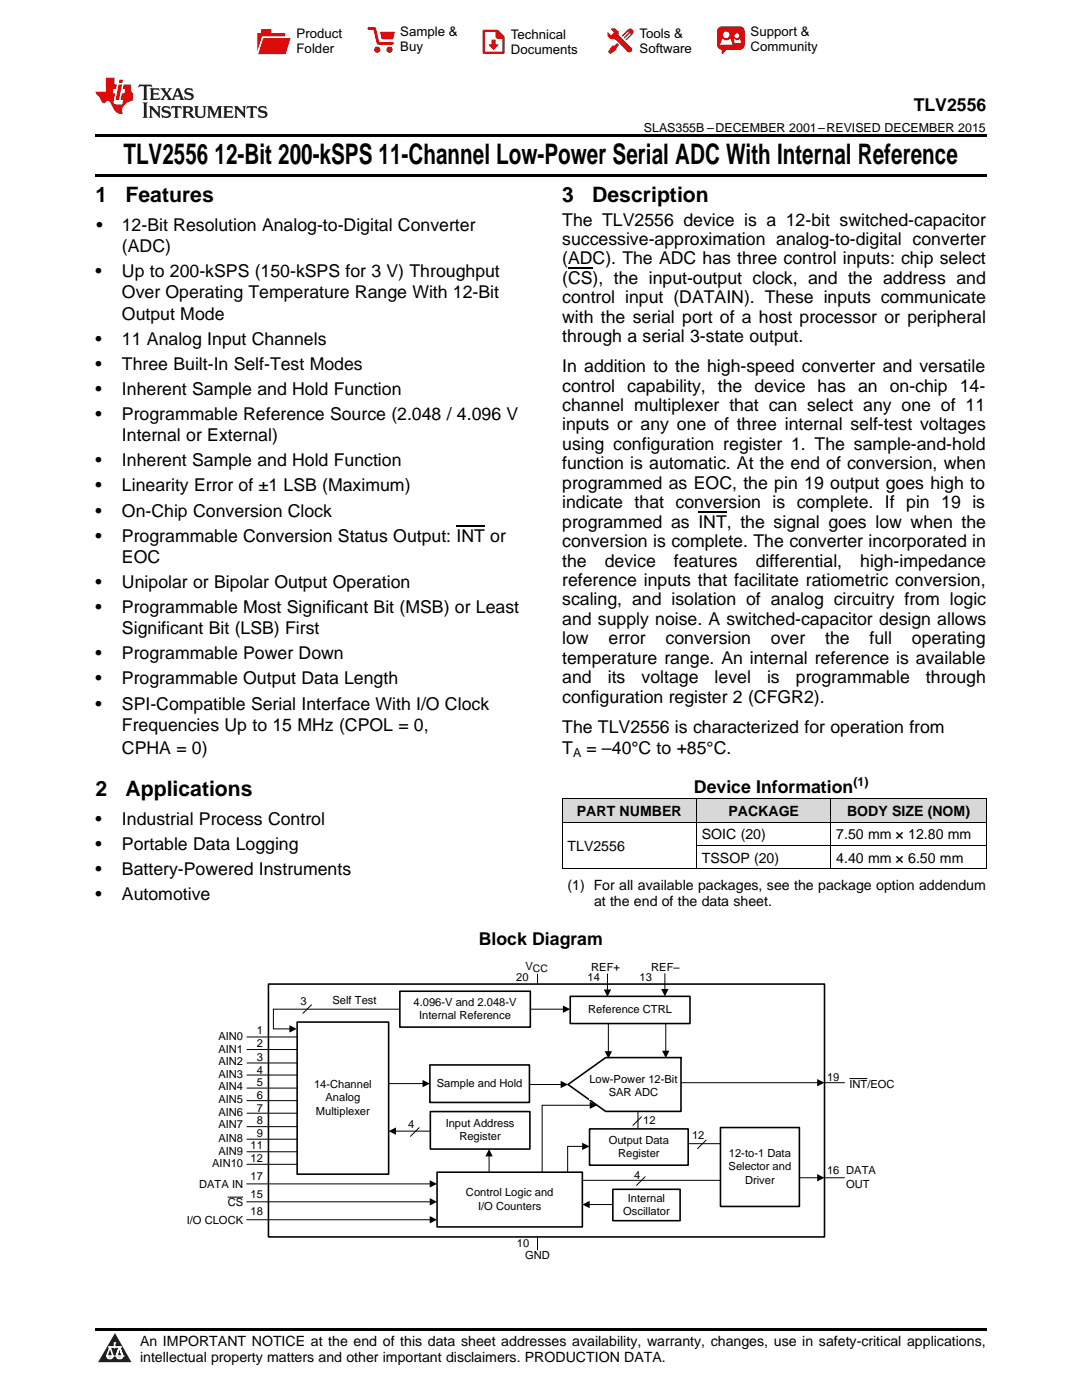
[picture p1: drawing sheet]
<svg xmlns="http://www.w3.org/2000/svg" width="216mm" height="279mm" viewBox="0 0 216 279" stroke-linecap="round" stroke-linejoin="round" font-family="sans-serif">
<defs><g id="words">
<g font-size="5.6">
<text x="24.6" y="32.8">TLV2556</text>
<text x="42.8" y="32.8">12-Bit 200-kSPS 11-Channel Low-Power Serial ADC With Internal Reference</text>
</g>
<g font-size="4.2">
<text x="19" y="40.4">1</text>
<text x="25" y="40.4">Features</text>
<text x="112.2" y="40.4">3</text>
<text x="118.2" y="40.4">Description</text>
<text x="19" y="158.9">2</text>
<text x="25" y="158.9">Applications</text>
</g>
<g font-size="3.5">
<text x="182.3" y="22.2">TLV2556</text>
<text x="19.2" y="46.1">•</text>
<text x="24.3" y="46.1">12-Bit Resolution Analog-to-Digital Converter</text>
<text x="112.2" y="45">The TLV2556 device is a 12-bit switched-capacitor</text>
<text x="24.3" y="50.3">(ADC)</text>
<text x="112.2" y="48.9">successive-approximation analog-to-digital converter</text>
<text x="112.2" y="52.8">(ADC). The ADC has three control inputs: chip select</text>
<text x="19" y="55.3">•</text>
<text x="24.3" y="55.3">Up to 200-kSPS (150-kSPS for 3 V) Throughput</text>
<text x="24.3" y="59.5">Over Operating Temperature Range With 12-Bit</text>
<text x="112.2" y="56.7">(CS), the input-output clock, and the address and</text>
<text x="24.3" y="63.8">Output Mode</text>
<text x="112.2" y="60.5">control input (DATAIN). These inputs communicate</text>
<text x="112.2" y="64.4">with the serial port of a host processor or peripheral</text>
<text x="19" y="68.8">•</text>
<text x="24.3" y="68.8">11 Analog Input Channels</text>
<text x="112.2" y="68.3">through a serial 3-state output.</text>
<text x="19" y="73.8">•</text>
<text x="24.3" y="73.8">Three Built-In Self-Test Modes</text>
<text x="112.2" y="74.3">In addition to the high-speed converter and versatile</text>
<text x="19" y="78.8">•</text>
<text x="19" y="83.8">•</text>
<text x="24.3" y="78.8">Inherent Sample and Hold Function</text>
<text x="24.3" y="83.8">Programmable Reference Source (2.048 / 4.096 V</text>
<text x="112.2" y="78.1">control capability, the device has an on-chip 14-</text>
<text x="112.2" y="82">channel multiplexer that can select any one of 11</text>
<text x="24.3" y="88.1">Internal or External)</text>
<text x="112.2" y="85.9">inputs or any one of three internal self-test voltages</text>
<text x="112.2" y="89.8">using configuration register 1. The sample-and-hold</text>
<text x="19" y="93.1">•</text>
<text x="24.3" y="93.1">Inherent Sample and Hold Function</text>
<text x="112.2" y="93.7">function is automatic. At the end of conversion, when</text>
<text x="19" y="98.1">•</text>
<text x="24.3" y="98.1">Linearity Error of ±1 LSB (Maximum)</text>
<text x="112.2" y="97.5">programmed as EOC, the pin 19 output goes high to</text>
<text x="112.2" y="101.4">indicate that conversion is complete. If pin 19 is</text>
<text x="19" y="103.1">•</text>
<text x="24.3" y="103.1">On-Chip Conversion Clock</text>
<text x="112.2" y="105.3">programmed as INT, the signal goes low when the</text>
<text x="19" y="108.1">•</text>
<text x="24.3" y="108.1">Programmable Conversion Status Output: INT or</text>
<text x="24.3" y="112.3">EOC</text>
<text x="112.2" y="109.2">conversion is complete. The converter incorporated in</text>
<text x="112.2" y="113.1">the</text>
<text x="120.7" y="113.1">device</text>
<text x="134.5" y="113.1">features</text>
<text x="150.8" y="113.1">differential,</text>
<text x="171.7" y="113.1">high-impedance</text>
<text x="19" y="117.3">•</text>
<text x="24.3" y="117.3">Unipolar or Bipolar Output Operation</text>
<text x="112.2" y="116.9">reference inputs that facilitate ratiometric conversion,</text>
<text x="19" y="122.3">•</text>
<text x="24.3" y="122.3">Programmable Most Significant Bit (MSB) or Least</text>
<text x="112.2" y="120.8">scaling, and isolation of analog circuitry from logic</text>
<text x="112.2" y="124.7">and supply noise. A switched-capacitor design allows</text>
<text x="19" y="131.6">•</text>
<text x="24.3" y="126.6">Significant Bit (LSB) First</text>
<text x="24.3" y="131.6">Programmable Power Down</text>
<text x="112.2" y="128.6">low</text>
<text x="121.4" y="128.6">error</text>
<text x="132.8" y="128.6">conversion</text>
<text x="153.8" y="128.6">over</text>
<text x="164.6" y="128.6">the</text>
<text x="173.5" y="128.6">full</text>
<text x="182" y="128.6">operating</text>
<text x="19" y="136.6">•</text>
<text x="24.3" y="136.6">Programmable Output Data Length</text>
<text x="112.2" y="132.5">temperature range. An internal reference is available</text>
<text x="112.2" y="136.3">and</text>
<text x="121.3" y="136.3">its</text>
<text x="128" y="136.3">voltage</text>
<text x="142.6" y="136.3">level</text>
<text x="153.1" y="136.3">is</text>
<text x="158.8" y="136.3">programmable</text>
<text x="184.8" y="136.3">through</text>
<text x="19" y="141.6">•</text>
<text x="24.3" y="141.6">SPI-Compatible Serial Interface With I/O Clock</text>
<text x="112.2" y="140.2">configuration register 2 (CFGR2).</text>
<text x="24.3" y="145.8">Frequencies Up to 15 MHz (CPOL = 0,</text>
<text x="112.2" y="146.2">The TLV2556 is characterized for operation from</text>
<text x="24.3" y="150.5">CPHA = 0)</text>
<text x="112.2" y="150.5">T</text>
<text x="117" y="150.5">= –40°C to +85°C.</text>
<text x="138.5" y="158.2">Device Information</text>
<text x="19" y="164.6">•</text>
<text x="24.3" y="164.6">Industrial Process Control</text>
<text x="19" y="169.6">•</text>
<text x="24.3" y="169.6">Portable Data Logging</text>
<text x="19" y="174.6">•</text>
<text x="19" y="179.6">•</text>
<text x="24.3" y="174.6">Battery-Powered Instruments</text>
<text x="24.3" y="179.6">Automotive</text>
<text x="95.5" y="188.6">Block Diagram</text>
</g>
<g font-size="2.8">
<text x="115.1" y="162.8">PART NUMBER</text>
<text x="140.1" y="167.5">SOIC (20)</text>
<text x="145.3" y="162.8">PACKAGE</text>
<text x="166.9" y="167.5">7.50 mm × 12.80 mm</text>
<text x="169" y="162.8">BODY SIZE (NOM)</text>
<text x="113.2" y="169.8">TLV2556</text>
<text x="140.1" y="172.2">TSSOP (20)</text>
<text x="166.9" y="172.2">4.40 mm × 6.50 mm</text>
<text x="113.2" y="177.7">(1) For all available packages, see the package option addendum</text>
<text x="118.5" y="180.8">at the end of the data sheet.</text>
<text x="27.9" y="268.6">An IMPORTANT NOTICE at the end of this data sheet addresses availability, warranty, changes, use in safety-critical applications,</text>
<text x="27.9" y="271.8">intellectual property matters and other important disclaimers. PRODUCTION DATA.</text>
</g>
<g font-size="2.6">
<text x="59.2" y="7.6">Product</text>
<text x="59.2" y="10.6">Folder</text>
<text x="79.9" y="7.3">Sample &amp;</text>
<text x="79.9" y="10.2">Buy</text>
<text x="101.9" y="7.8">Technical</text>
<text x="101.9" y="10.8">Documents</text>
<text x="127.6" y="7.6">Tools &amp;</text>
<text x="127.6" y="10.6">Software</text>
<text x="149.8" y="7.2">Support &amp;</text>
<text x="149.8" y="10.2">Community</text>
</g>
<g font-size="2.5">
<text x="128.5" y="26.3">SLAS355B –DECEMBER 2001–REVISED DECEMBER 2015</text>
<text x="114.3" y="151.2">A</text>
<text x="170.3" y="156.8">(1)</text>
</g>
<g font-size="2.2">
<text x="103" y="195.8">20</text>
<text x="104.8" y="193.6">VCC</text>
<text x="117.2" y="195.8">14</text>
<text x="118" y="193.8">REF+</text>
<text x="127.6" y="195.8">13</text>
<text x="130" y="193.8">REF±</text>
<text x="60" y="200.6">3</text>
<text x="66.4" y="200.4">Self Test</text>
<text x="82.5" y="200.7">4.096-V and 2.048-V</text>
<text x="83.6" y="203.4">Internal Reference</text>
<text x="117.4" y="202.2">Reference CTRL</text>
<text x="43.6" y="207.6">AIN0</text>
<text x="51.2" y="206.4">1</text>
<text x="51.2" y="209">2</text>
<text x="43.6" y="210.1">AIN1</text>
<text x="43.6" y="212.6">AIN2</text>
<text x="43.6" y="215.2">AIN3</text>
<text x="51.2" y="211.7">3</text>
<text x="51.2" y="214.2">4</text>
<text x="165" y="215.7">19</text>
<text x="43.6" y="217.6">AIN4</text>
<text x="43.6" y="220.2">AIN5</text>
<text x="51.2" y="216.7">5</text>
<text x="51.2" y="219.3">6</text>
<text x="51.2" y="221.9">7</text>
<text x="62.7" y="217.1">14-Channel</text>
<text x="65" y="219.8">Analog</text>
<text x="87.2" y="216.9">Sample and Hold</text>
<text x="117.6" y="216.1">Low-Power 12-Bit</text>
<text x="121.5" y="218.8">SAR ADC</text>
<text x="169.5" y="217.1">INT/EOC</text>
<text x="43.6" y="222.6">AIN6</text>
<text x="43.6" y="225.2">AIN7</text>
<text x="43.6" y="227.8">AIN8</text>
<text x="51.2" y="224.4">8</text>
<text x="51.2" y="226.9">9</text>
<text x="63" y="222.5">Multiplexer</text>
<text x="81.4" y="225.2">4</text>
<text x="88.9" y="224.9">Input Address</text>
<text x="91.7" y="227.6">Register</text>
<text x="128.3" y="224.3">12</text>
<text x="138.1" y="227.3">12</text>
<text x="42.3" y="232.9">AIN10</text>
<text x="43.6" y="230.5">AIN9</text>
<text x="50" y="229.4">11</text>
<text x="50" y="231.9">12</text>
<text x="121.5" y="228.2">Output Data</text>
<text x="123.3" y="230.9">Register</text>
<text x="145.4" y="233.6">Selector and</text>
<text x="145.4" y="230.9">12-to-1 Data</text>
<text x="39.7" y="237.1">DATA IN</text>
<text x="50" y="235.5">17</text>
<text x="50" y="239.1">15</text>
<text x="93" y="238.7">Control Logic and</text>
<text x="125.3" y="239.8">Internal</text>
<text x="126.5" y="235.2">4</text>
<text x="148.7" y="236.2">Driver</text>
<text x="165" y="234.3">16 DATA</text>
<text x="168.8" y="237.1">OUT</text>
<text x="37.3" y="244.3">I/O CLOCK</text>
<text x="45.4" y="240.8">CS</text>
<text x="50" y="242.6">18</text>
<text x="95.4" y="241.4">I/O Counters</text>
<text x="124.4" y="242.5">Oscillator</text>
<text x="103.2" y="248.9">10</text>
<text x="104.8" y="251.3">GND</text>
</g>
</g></defs>
<g fill="#d8d8d8">
<path d="M112.2 159.5h26.8v4.6h-26.8z"/>
<path d="M139 159.5h26.8v4.6h-26.8z"/>
<path d="M165.8 159.5h31v4.6h-31z"/>
</g>
<path d="M22.9 266l3.3 5.9h-6.6z" fill="#231f20"/>
<path d="M21.3 270.6h1.2l-.3 .5h-.3a.53 .53 0 0 1-.6-.5z" fill-rule="evenodd" fill="#fff"/>
<path d="M21.3 270.6h1.2l-.3 .5h-.3a.53 .53 0 0 1-.6-.5z" fill="none" stroke="#231f20" stroke-width=".33"/>
<path d="M21.3 270.6l1.2 .1-.3 .4h-.5z" fill="none" stroke="#fff" stroke-width=".33"/>
<path d="M22.9 268.9h.1" fill="none" stroke="#fff" stroke-width=".33"/>
<path d="M22.9 268v.9z" fill="#fff"/>
<path d="M22.9 268v.9z" fill="none" stroke="#fff" stroke-width=".33"/>
<circle cx="22.9" cy="268" r=".16" fill="#fff"/>
<path d="M21.8 268.8h.1" fill="none" stroke="#fff" stroke-width=".33"/>
<path d="M21.8 268.8h2.2z" fill="#fff"/>
<path d="M21.8 268.8h2.2z" fill="none" stroke="#fff" stroke-width=".33"/>
<circle cx="24" cy="268.8" r=".16" fill="#fff"/>
<path d="M23.2 270.6h.1" fill="none" stroke="#fff" stroke-width=".33"/>
<path d="M23.8 268.8l-.6 1.8z" fill="#fff"/>
<path d="M23.8 268.8l-.6 1.8z" fill="none" stroke="#fff" stroke-width=".33"/>
<path d="M23.8 268.8l.7 1.8z" fill="#fff"/>
<path d="M23.8 268.8l.7 1.8z" fill="none" stroke="#fff" stroke-width=".33"/>
<path d="M24.4 270.6h.1" fill="none" stroke="#fff" stroke-width=".33"/>
<circle cx="21.3" cy="270.6" r=".16" fill="#fff"/>
<path d="M22 268.8l-.7 1.8z" fill="#fff"/>
<path d="M22 268.8l-.7 1.8z" fill="none" stroke="#fff" stroke-width=".33"/>
<path d="M22 268.8l.5 1.8z" fill="#fff"/>
<path d="M22 268.8l.5 1.8z" fill="none" stroke="#fff" stroke-width=".33"/>
<circle cx="22.5" cy="270.6" r=".16" fill="#fff"/>
<path d="M23.3 270.6h1.2a.63 .63 0 0 1-.6 .5 .63 .63 0 0 1-.6-.5z" fill-rule="evenodd" fill="#fff"/>
<path d="M23.3 270.6h1.2a.63 .63 0 0 1-.6 .5 .63 .63 0 0 1-.6-.5z" fill="none" stroke="#231f20" stroke-width=".33"/>
<path d="M23.3 270.6h1.2l-.4 .5h-.5z" fill="none" stroke="#fff" stroke-width=".33"/>
<path d="M23.2 270.6h.1" fill="none" stroke="#fff" stroke-width=".33"/>
<circle cx="24.5" cy="270.6" r=".16" fill="#fff"/>
<path d="M19 265.1h177.8v.5h-177.8z" fill="#000"/>
<path d="M53.6 196.4h110.9v50.5h-110.9zM79.8 197.8h26v7.2h-26zM113.8 198.8h23.9v5.5h-23.9zM59.3 204h18.2v30.3h-18.2zM85.8 212.5h19.8v7.5h-19.8zM113.3 216.4l7.6-5.3h15v10.7h-15zM85.9 221.8h19.8v7.5h-19.8zM87.2 233.9h29v11h-29zM117.6 225.3h19.7v7.2h-19.7zM122.3 237.4h13.4v6.2h-13.4zM143.8 225h15.7v15.8h-15.7z" fill="none" stroke="#000" stroke-width=".32"/>
<path d="M117.6 214.1h17.6v5.4h-17.6z" fill-rule="evenodd" fill="#fff"/>
<g fill="none" stroke="#000" stroke-width=".2">
<path d="M112.2 159.4h84.6M112.2 159.5v13.9M138.9 159.5v13.9M165.8 159.5v13.9M196.8 159.5v13.9M112.2 173.4h84.6M112.2 164.1h84.6M139 168.7h57.8M107.3 194.4v1.8M121.2 194.4v3.3M132.7 194.3v3.3M49.3 207h10"/>
<path d="M49.3 209.5h10M49.3 212.1h10M49.3 214.5h10M49.3 217.2h10M49.3 219.7h10M54.6 205.3h3.3M62.2 200.5l-1.8 1.7M77.6 216.3h6.9M79.8 201.4h-25.2v3.9M105.6 216.4h6.5M105.8 201.4h6.7M121.4 204.4v5.6"/>
<path d="M132.8 204.3v5.6M136 216.1h27.2M164.5 216.1h4M169.5 215.3h3.6M45.4 238.9h3.1M49.2 236.3h36.7M49.2 239.8h36.7M49.3 222.2h10M49.3 224.8h10M49.3 227.4h10M49.3 229.9h10M49.3 232.4h10"/>
<path d="M78.8 225.7h7M83.6 225.1l-1.7 1.7M97.6 230.6v3.3M116.2 235.6h27.5M116.4 228.8h-3.1v5.1M117.9 220.6h-9.7v13.4M127.3 221.8v3.4M128 222.9l-1.7 1.7M128.7 234.8l-1.7 1.8M137.3 228.2h6.5M140.9 227.5l-1.7 1.7M159.7 235h3.5"/>
<path d="M164.5 235h4M49.2 243.4h36.7M107.3 246.8v2.7M117.5 240.4h4.7"/>
</g>
<g fill="#000">
<path d="M120.5 197.5h1.4l-.7 1.4zM131.9 197.4h1.5l-.7 1.4zM57.8 204.6l1.4 .7-1.4 .8zM84.3 215.5l1.5 .8-1.5 .7zM111.9 215.7l1.4 .7-1.4 .8zM112.3 200.7l1.5 .7-1.5 .7zM117.7 219.8l1.4 .8-1.4 .7zM120.7 209.8h1.4l-.7 1.5zM132.1 209.7h1.5l-.8 1.5zM163.1 215.3l1.4 .8-1.4 .7zM77.5 225.7l1.5-.7v1.5zM85.7 235.5l1.5 .8-1.5 .7z"/>
<path d="M85.7 239.1l1.5 .7-1.5 .8zM97.6 229.3l.7 1.5h-1.4zM116.2 228.1l1.4 .7-1.4 .7zM163.1 234.3l1.4 .7-1.4 .8zM85.7 242.7l1.5 .7-1.5 .8zM116.2 240.4l1.5-.7v1.4z"/>
</g>
<path d="M19 34.8h177.8v.5h-177.8zM19 26.8h177.8v.6h-177.8z" fill="#000"/>
<path d="M27.7 16.9l-.1 .6 .6-.3h.5v.2v2.2l-.2 .4h1l-.2-.4v-2.2v-.2h.5l.6 .3-.2-.6zM29.9 17.6l.2 .4v1.6l-.2 .4h1.9l.1-.6a1.09 1.09 0 0 1-1.3 .1v-.6h.6l.4 .2v-.7l-.2 .2h-.8v-.6l.2-.1a1.01 1.01 0 0 1 1 .3l-.1-.6zM32 17.6l.9 1.2-1 1.2h.9l-.2-.3 .5-.7 .5 .7-.3 .3h1.7l-.2-.3 .1-.4h1l.1 .4-.2 .3h1l-.3-.4-.7-2h-.5l-1 2.2-.8-1.1 .9-1.1h-.9l.2 .2-.4 .7-.4-.7 .2-.2zM35.4 18l.4 1h-.8zM37 17.7a.66 .66 0 0 0-.2 .8 .66 .66 0 0 0 .6 .4l.7 .2 .1 .2a.8 .8 0 0 1-.7 .4 .8 .8 0 0 1-.7-.5l.1 .8 .2-.2a.94 .94 0 0 0 1.1 .1 .94 .94 0 0 0 .4-.9 1.48 1.48 0 0 0-1.3-.6v-.4a1.1 1.1 0 0 1 1.2 .2l-.2-.6-.2 .1-.5-.1zM28.5 20.4l.2 .4v2.3l-.2 .4h1l-.2-.4v-2.3l.2-.4zM29.7 21.2l.2 .4v1.5l-.2 .4h.8l-.3-.4 .1-1.3 1.6 1.8v-2l.2-.4h-.7l.2 .2v1.1l-1.2-1.3zM32.5 21.3a.66 .66 0 0 0-.2 .8 .66 .66 0 0 0 .6 .4l.6 .2 .2 .2a.8 .8 0 0 1-.8 .4 .8 .8 0 0 1-.7-.5l.2 .7 .2-.1a.94 .94 0 0 0 1 .1 .94 .94 0 0 0 .5-1 1.47 1.47 0 0 0-1.3-.6l-.1-.3a1.1 1.1 0 0 1 1.3 .2l-.2-.6-.2 .1-.5-.2zM34.3 21.2l-.2 .6a.64 .64 0 0 1 .8-.3v1.6l-.2 .4h1l-.3-.4 .1-1.6a.66 .66 0 0 1 .8 .3l-.2-.6zM36.3 21.2l.3 .4v1.5l-.3 .4h1l-.2-.2v-.7h.5l.1 .1a.8 .8 0 0 0 1.2 .7l-1-1a.62 .62 0 0 0 .6-.5 .62 .62 0 0 0-.6-.7zM37.1 21.5h.1a.48 .48 0 0 1 .6 0 .48 .48 0 0 1 .1 .6l-.2 .1-.6 .1zM38.7 21.2l.2 .2a2.29 2.29 0 0 0 .4 2 1.05 1.05 0 0 0 1.7-.7v-1.3l.2-.2h-.8l.2 .4v1.1a.61 .61 0 0 1-.6 .6 .61 .61 0 0 1-.6-.6v-1.1l.3-.4zM41.3 21.2l.3 .4v1.5l-.3 .4h.8l-.2-.4v-1.4l.8 1.9 .9-1.9v1.4l-.2 .4h.9l-.2-.4v-1.5l.2-.4h-.8l-.7 1.5-.6-1.5zM44.5 21.2l.2 .4v1.5l-.2 .4h1.9l.2-.6a1.1 1.1 0 0 1-1.4 .2v-.7h.6l.4 .2v-.6l-.2 .1-.8 .1v-.6l.2-.1a1.02 1.02 0 0 1 1.1 .2l-.2-.5zM46.7 21.2l.2 .4v1.5l-.2 .4h.8l-.3-.4 .1-1.3 1.6 1.8v-2l.2-.4h-.7l.2 .2v1.1l-1.2-1.3zM49.3 21.2l-.1 .6a.64 .64 0 0 1 .8-.3v1.6l-.3 .4h1l-.2-.4v-1.6a.66 .66 0 0 1 .8 .3l-.1-.6zM51.7 21.3a.66 .66 0 0 0-.2 .7 .66 .66 0 0 0 .7 .5l.6 .2 .1 .2a.8 .8 0 0 1-.7 .4 .8 .8 0 0 1-.7-.5l.1 .7 .2-.1a.94 .94 0 0 0 1.1 .1 .94 .94 0 0 0 .4-1 1.48 1.48 0 0 0-1.2-.6l-.1-.3a1.1 1.1 0 0 1 1.2 .2l-.2-.6-.1 .1-.6-.2z" fill="#231f20"/>
<path d="M21.1 15.5v2.8h-2v.4l.9 .9a.96 .96 0 0 0 1 1 .59 .59 0 0 1 .5-.4 .59 .59 0 0 1 .5 .3l.4 .8a1.61 1.61 0 0 0 2.1 1.3 1.63 1.63 0 0 1 1.1-2.2l.9-.3v-1.5a1.6 1.6 0 0 1-.4-1.7h-1.4l-.2 .9h.5l-.2 .8h-.5l-.2 1v.3h.5l-.2 .9h-.7a.74 .74 0 0 1-1-.6l.3-1.6h-.5l.2-.8h.5l.1-.9h-.4v-1.4zM23.7 16.9l-.7 3h.8l.6-3zM23.8 15.9l-.1 .7h.7l.2-.7z" fill="#ee1d23"/>
<g fill="#d60000">
<path d="M52.1 5.8h2v.8h2.8v4.2h-5.5v-4.2h.7z" fill-rule="evenodd"/>
<path d="M52.4 7.5h5.6l-1 3.3h-5.6z" fill-rule="evenodd"/>
</g>
<path d="M52.4 7.4h5.7l-.1 .1h-5.5l-1.1 3.3z" fill-rule="evenodd" fill="#fff"/>
<path d="M52.4 7.4h5.7l-.1 .1h-5.5l-1.1 3.3z" fill="none" stroke="#fff" stroke-width=".2"/>
<path d="M73.6 5.7h1.1l.7 2.9h2.9" fill="none" stroke="#d60000" stroke-width=".55"/>
<g fill="#d60000">
<path d="M75.8 6.3h3l-.4 1.6h-2.2z" fill-rule="evenodd"/>
<circle cx="75.3" cy="9.9" r=".62"/>
<circle cx="77.7" cy="9.9" r=".62"/>
</g>
<path d="M96.5 6.2h2.7l1.3 1.2v3.1h-4z" fill="none" stroke="#d60000" stroke-width=".44"/>
<g fill="#d60000">
<path d="M98.1 7.9h.8v1h.5l-.9 1.1-1-1v-.1h.6z" fill-rule="evenodd"/>
<path d="M98.9 6.2h.3l1.3 1.2v.4h-1.3l-.3-.4z" fill-rule="evenodd"/>
<path d="M121.9 5.7h.8l.7 .6 .1 .7 2.5 2.5-.8 .8-2.3-2.3-1.1-.2-.6-.6v-.8l.7 .6 .5-.4v-.2l-.5-.5z" fill-rule="evenodd"/>
<path d="M122.2 9.1h.4l.5-.5 .4 .4-.5 .5v.4l-1.2 .9-.5-.5z" fill-rule="evenodd"/>
<path d="M125.3 5.9a.67 .67 0 0 1 .9 0 .67 .67 0 0 1 0 .9z" fill-rule="evenodd"/>
<path d="M125.3 5.9l.9 .9-1.2 1.2h-.2v-.2l1-.9v-.2h-.2l-.9 1h-.2v-.2l.9-1 .1-.2h-.3l-.9 1h-.2v-.2z" fill-rule="evenodd"/>
<circle cx="125.6" cy="9.9" r=".54"/>
</g>
<path d="M123.3 6.3v.7" fill="none" stroke="#d60000" stroke-width=".2"/>
<g fill="#d60000">
<path d="M143.4 5.5l.6-.2h3.6a.95 .95 0 0 1 1 .9v2.8a.95 .95 0 0 1-1 .9h-3.6a.95 .95 0 0 1-.9-.9v-2.8z" fill-rule="evenodd"/>
<path d="M144 9.9h.9l-.7 .9h-.2z" fill-rule="evenodd"/>
</g>
<g fill="#fff">
<path d="M146.6 8.6h1.3z"/>
<path d="M144.1 7.8h.3l.1 .2h.8l.2-.2h.3l.4 1.1h-2.5z" fill-rule="evenodd"/>
<path d="M146.4 7.8h.3l.1 .2h.5l.2-.2h.2l.2 .8h-1.3z" fill-rule="evenodd"/>
<circle cx="144.9" cy="6.9" r=".65"/>
<circle cx="147" cy="7.1" r=".48"/>
</g>
<path d="M113.3 53.5h4.9M91.1 105h5.7M139.3 102.2h5.7" fill="none" stroke="#000" stroke-width=".25"/>
<use href="#words"/>
</svg>
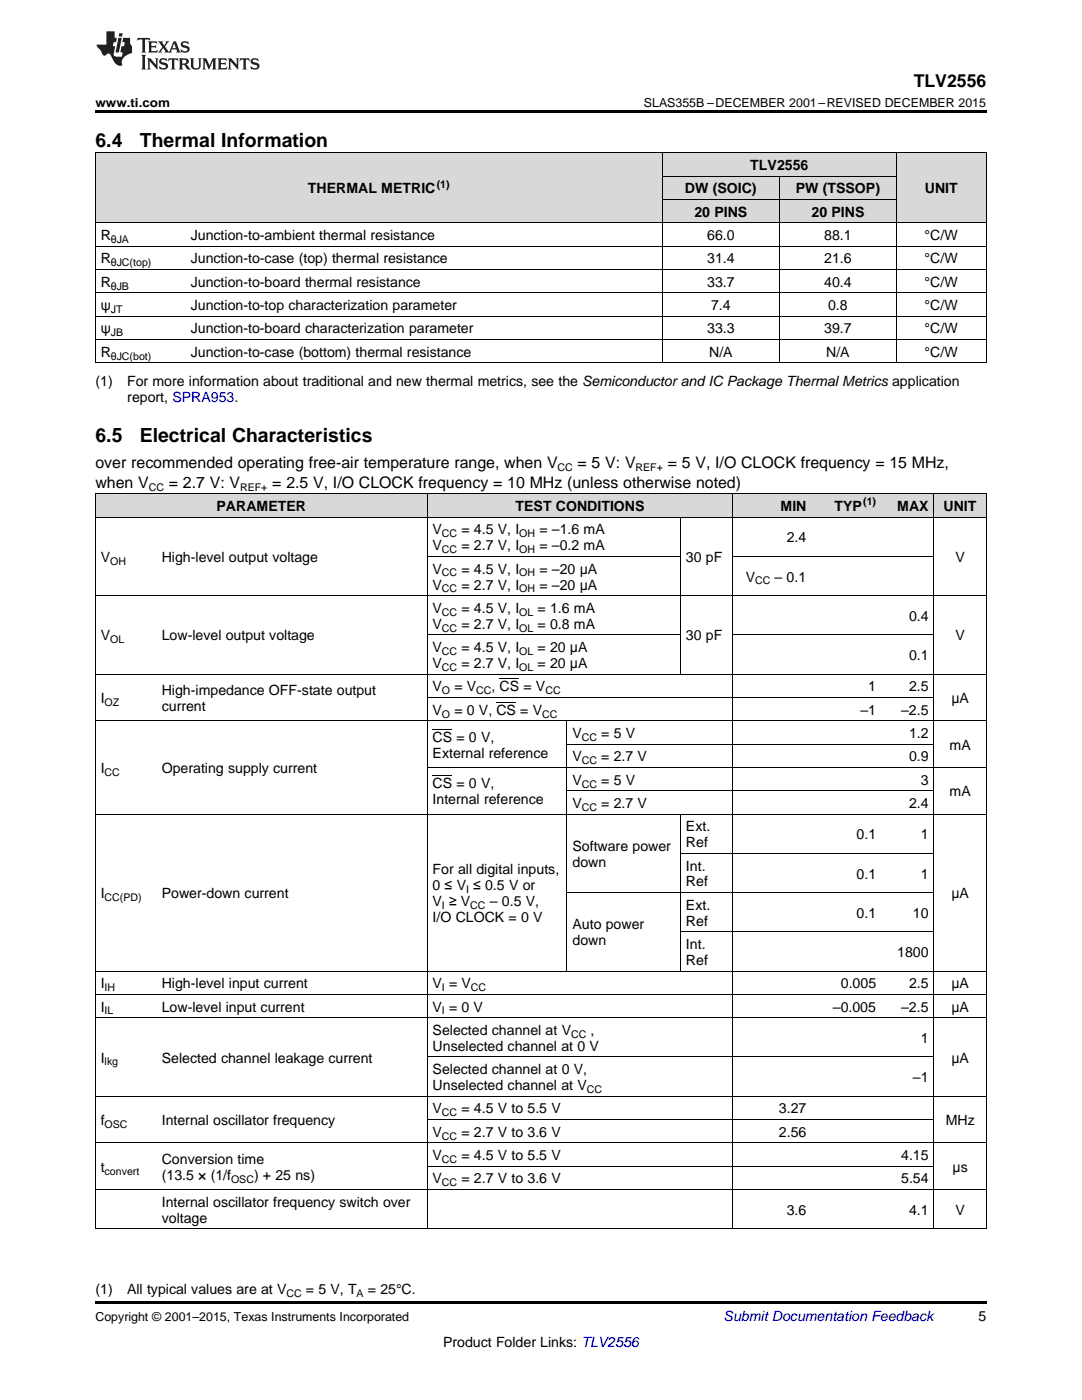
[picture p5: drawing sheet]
<svg xmlns="http://www.w3.org/2000/svg" width="216mm" height="279mm" viewBox="0 0 216 279" stroke-linecap="round" stroke-linejoin="round" font-family="sans-serif">
<defs><g id="words">
<g font-size="3.9">
<text x="19" y="29.3">6.4</text>
<text x="27.9" y="29.3">Thermal Information</text>
<text x="19" y="88.3">6.5</text>
<text x="27.9" y="88.3">Electrical Characteristics</text>
</g>
<text font-size="3.5" x="182.3" y="17.3">TLV2556</text>
<g font-size="3.2">
<text x="19" y="93.5">over recommended operating free-air temperature range, when V</text>
<text x="115.3" y="93.5">= 5 V: V</text>
<text x="133.2" y="93.5">= 5 V, I/O CLOCK frequency = 15 MHz,</text>
<text x="19" y="97.3">when V</text>
<text x="33.7" y="97.3">= 2.7 V: V</text>
<text x="54.3" y="97.3">= 2.5 V, I/O CLOCK frequency = 10 MHz (unless otherwise noted)</text>
</g>
<g font-size="2.8">
<text x="149.7" y="33.9">TLV2556</text>
<text x="61.5" y="38.6">THERMAL METRIC</text>
<text x="136.7" y="38.6">DW (SOIC)</text>
<text x="158.8" y="38.6">PW (TSSOP)</text>
<text x="184.5" y="38.6">UNIT</text>
<text x="20.1" y="47.9">R</text>
<text x="38.1" y="47.9">Junction-to-ambient thermal resistance</text>
<text x="138.6" y="43.3">20 PINS</text>
<text x="141.1" y="47.9">66.0</text>
<text x="161.9" y="43.3">20 PINS</text>
<text x="164.5" y="47.9">88.1</text>
<text x="184.5" y="47.9">°C/W</text>
<text x="20.1" y="52.6">R</text>
<text x="38.1" y="52.6">Junction-to-case (top) thermal resistance</text>
<text x="141.1" y="52.6">31.4</text>
<text x="164.5" y="52.6">21.6</text>
<text x="184.5" y="52.6">°C/W</text>
<text x="20.1" y="57.2">R</text>
<text x="38.1" y="57.2">Junction-to-board thermal resistance</text>
<text x="141.1" y="57.2">33.7</text>
<text x="164.5" y="57.2">40.4</text>
<text x="184.5" y="57.2">°C/W</text>
<text x="20.1" y="61.9">ψ</text>
<text x="38.1" y="61.9">Junction-to-top characterization parameter</text>
<text x="141.9" y="61.9">7.4</text>
<text x="165.2" y="61.9">0.8</text>
<text x="184.5" y="61.9">°C/W</text>
<text x="20.1" y="66.5">ψ</text>
<text x="20.1" y="71.2">R</text>
<text x="38.1" y="66.5">Junction-to-board characterization parameter</text>
<text x="38.1" y="71.2">Junction-to-case (bottom) thermal resistance</text>
<text x="141.1" y="66.5">33.3</text>
<text x="141.5" y="71.2">N/A</text>
<text x="164.5" y="66.5">39.7</text>
<text x="164.9" y="71.2">N/A</text>
<text x="184.5" y="66.5">°C/W</text>
<text x="184.5" y="71.2">°C/W</text>
<text x="19" y="77">(1)</text>
<text x="25.4" y="77">For more information about traditional and new thermal metrics, see the Semiconductor and IC Package Thermal Metrics application</text>
<text x="25.4" y="80.2">report, SPRA953.</text>
<text x="43.2" y="102">PARAMETER</text>
<text x="102.9" y="102">TEST CONDITIONS</text>
<text x="155.8" y="102">MIN</text>
<text x="166.5" y="102">TYP</text>
<text x="179" y="102">MAX</text>
<text x="188.3" y="102">UNIT</text>
<text x="86.3" y="106.6">V</text>
<text x="92.1" y="106.6">= 4.5 V, I</text>
<text x="107.6" y="106.6">= –1.6 mA</text>
<text x="20.1" y="112.1">V</text>
<text x="32.3" y="112.1">High-level output voltage</text>
<text x="86.3" y="109.8">V</text>
<text x="92.1" y="109.8">= 2.7 V, I</text>
<text x="107.6" y="109.8">= –0.2 mA</text>
<text x="136.9" y="112.1">30 pF</text>
<text x="157" y="108.2">2.4</text>
<text x="190.6" y="112.1">V</text>
<text x="86.3" y="114.5">V</text>
<text x="86.3" y="117.7">V</text>
<text x="92.1" y="114.5">= 4.5 V, I</text>
<text x="92.1" y="117.7">= 2.7 V, I</text>
<text x="107.6" y="114.5">= –20 μA</text>
<text x="107.6" y="117.7">= –20 μA</text>
<text x="148.8" y="116.1">V</text>
<text x="154.6" y="116.1">– 0.1</text>
<text x="86.3" y="122.3">V</text>
<text x="86.3" y="125.5">V</text>
<text x="92.1" y="122.3">= 4.5 V, I</text>
<text x="92.1" y="125.5">= 2.7 V, I</text>
<text x="107.3" y="122.3">= 1.6 mA</text>
<text x="107.3" y="125.5">= 0.8 mA</text>
<text x="181.4" y="123.9">0.4</text>
<text x="20.1" y="127.8">V</text>
<text x="32.3" y="127.8">Low-level output voltage</text>
<text x="86.3" y="130.1">V</text>
<text x="92.1" y="130.1">= 4.5 V, I</text>
<text x="107.3" y="130.1">= 20 μA</text>
<text x="136.9" y="127.8">30 pF</text>
<text x="181.4" y="131.7">0.1</text>
<text x="190.6" y="127.8">V</text>
<text x="86.3" y="133.3">V</text>
<text x="86.3" y="138">V</text>
<text x="90.7" y="138">= V</text>
<text x="92.1" y="133.3">= 2.7 V, I</text>
<text x="98.1" y="138">, CS = V</text>
<text x="107.3" y="133.3">= 20 μA</text>
<text x="173.2" y="138">1</text>
<text x="181.4" y="138">2.5</text>
<text x="20.1" y="140.3">I</text>
<text x="32.3" y="138.7">High-impedance OFF-state output</text>
<text x="32.3" y="141.9">current</text>
<text x="86.3" y="142.6">V</text>
<text x="90.7" y="142.6">= 0 V, CS = V</text>
<text x="171.7" y="142.6">–1</text>
<text x="179.8" y="142.6">–2.5</text>
<text x="189.8" y="140.3">μA</text>
<text x="86.3" y="148">CS = 0 V,</text>
<text x="114.2" y="147.3">V</text>
<text x="120" y="147.3">= 5 V</text>
<text x="181.4" y="147.3">1.2</text>
<text x="189.5" y="149.6">mA</text>
<text x="20.1" y="154.3">I</text>
<text x="32.3" y="154.3">Operating supply current</text>
<text x="86.3" y="151.2">External reference</text>
<text x="114.2" y="151.9">V</text>
<text x="120" y="151.9">= 2.7 V</text>
<text x="181.4" y="151.9">0.9</text>
<text x="86.3" y="157.3">CS = 0 V,</text>
<text x="86.3" y="160.5">Internal reference</text>
<text x="114.2" y="156.6">V</text>
<text x="114.2" y="161.3">V</text>
<text x="120" y="156.6">= 5 V</text>
<text x="120" y="161.3">= 2.7 V</text>
<text x="181.4" y="161.3">2.4</text>
<text x="183.7" y="156.6">3</text>
<text x="189.5" y="158.9">mA</text>
<text x="136.9" y="165.9">Ext.</text>
<text x="170.9" y="167.5">0.1</text>
<text x="183.7" y="167.5">1</text>
<text x="114.2" y="169.8">Software power</text>
<text x="114.2" y="173">down</text>
<text x="136.9" y="169.1">Ref</text>
<text x="136.9" y="173.7">Int.</text>
<text x="20.1" y="179.2">I</text>
<text x="32.3" y="179.2">Power-down current</text>
<text x="86.3" y="174.5">For all digital inputs,</text>
<text x="86.3" y="177.7">0 ≤ V ≤ 0.5 V or</text>
<text x="136.9" y="176.9">Ref</text>
<text x="170.9" y="175.3">0.1</text>
<text x="183.7" y="175.3">1</text>
<text x="189.8" y="179.2">μA</text>
<text x="86.3" y="180.8">V ≥ V</text>
<text x="86.3" y="184">I/O CLOCK = 0 V</text>
<text x="97.7" y="180.8">– 0.5 V,</text>
<text x="114.2" y="185.5">Auto power</text>
<text x="136.9" y="181.6">Ext.</text>
<text x="136.9" y="184.7">Ref</text>
<text x="170.9" y="183.2">0.1</text>
<text x="182.2" y="183.2">10</text>
<text x="114.2" y="188.7">down</text>
<text x="136.9" y="189.4">Int.</text>
<text x="179" y="191">1800</text>
<text x="20.1" y="197.2">I</text>
<text x="32.3" y="197.2">High-level input current</text>
<text x="86.3" y="197.2">V = V</text>
<text x="136.9" y="192.6">Ref</text>
<text x="167.8" y="197.2">0.005</text>
<text x="181.4" y="197.2">2.5</text>
<text x="189.8" y="197.2">μA</text>
<text x="20.1" y="201.9">I</text>
<text x="32.3" y="201.9">Low-level input current</text>
<text x="86.3" y="201.9">V = 0 V</text>
<text x="166.2" y="201.9">–0.005</text>
<text x="179.8" y="201.9">–2.5</text>
<text x="189.8" y="201.9">μA</text>
<text x="86.3" y="206.6">Selected channel at V</text>
<text x="86.3" y="209.7">Unselected channel at 0 V</text>
<text x="117.8" y="206.6">,</text>
<text x="183.7" y="208.1">1</text>
<text x="20.1" y="212.1">I</text>
<text x="32.3" y="212.1">Selected channel leakage current</text>
<text x="86.3" y="214.4">Selected channel at 0 V,</text>
<text x="182.2" y="216">–1</text>
<text x="189.8" y="212.1">μA</text>
<text x="86.3" y="217.6">Unselected channel at V</text>
<text x="20.1" y="224.5">f</text>
<text x="32.3" y="224.5">Internal oscillator frequency</text>
<text x="86.3" y="222.2">V</text>
<text x="86.3" y="226.9">V</text>
<text x="92.1" y="222.2">= 4.5 V to 5.5 V</text>
<text x="92.1" y="226.9">= 2.7 V to 3.6 V</text>
<text x="155.4" y="222.2">3.27</text>
<text x="155.4" y="226.9">2.56</text>
<text x="188.7" y="224.5">MHz</text>
<text x="20.1" y="233.9">t</text>
<text x="32.3" y="232.3">Conversion time</text>
<text x="86.3" y="231.5">V</text>
<text x="92.1" y="231.5">= 4.5 V to 5.5 V</text>
<text x="179.8" y="231.5">4.15</text>
<text x="190.1" y="233.9">μs</text>
<text x="32.3" y="235.4">(13.5 × (1/f</text>
<text x="50.7" y="235.4">) + 25 ns)</text>
<text x="86.3" y="236.2">V</text>
<text x="92.1" y="236.2">= 2.7 V to 3.6 V</text>
<text x="179.8" y="236.2">5.54</text>
<text x="32.3" y="240.8">Internal oscillator frequency switch over</text>
<text x="32.3" y="244">voltage</text>
<text x="157" y="242.4">3.6</text>
<text x="181.4" y="242.4">4.1</text>
<text x="190.6" y="242.4">V</text>
<text x="19" y="258.2">(1)</text>
<text x="25.4" y="258.2">All typical values are at V</text>
<text x="61" y="258.2">= 5 V, T</text>
<text x="73.4" y="258.2">= 25°C.</text>
<text x="195.3" y="263.6">5</text>
<text x="88.4" y="268.9">Product Folder Links: TLV2556</text>
</g>
<text font-size="2.8" fill="#0000c8" x="144.4" y="263.6">Submit Documentation Feedback</text>
<g font-size="2.5">
<text x="19" y="21.4">www.ti.com</text>
<text x="128.5" y="21.4">SLAS355B –DECEMBER 2001–REVISED DECEMBER 2015</text>
<text x="19" y="263.6">Copyright © 2001–2015, Texas Instruments Incorporated</text>
</g>
<g font-size="2.1">
<text x="87.1" y="37.5">(1)</text>
<text x="22.1" y="48.5">θJA</text>
<text x="22.1" y="53.1">θJC(top)</text>
<text x="22.1" y="57.8">θJB</text>
<text x="22.1" y="62.4">JT</text>
<text x="22.1" y="67.1">JB</text>
<text x="22.1" y="71.8">θJC(bot)</text>
<text x="111.3" y="94.1">CC</text>
<text x="126.8" y="94.1">REF+</text>
<text x="29.7" y="98">CC</text>
<text x="47.9" y="98">REF+</text>
<text x="172.2" y="100.9">(1)</text>
<text x="88.2" y="107.2">CC</text>
<text x="103.6" y="107.2">OH</text>
<text x="22" y="112.7">OH</text>
<text x="88.2" y="110.4">CC</text>
<text x="103.6" y="110.4">OH</text>
<text x="88.2" y="115">CC</text>
<text x="88.2" y="118.2">CC</text>
<text x="103.6" y="115">OH</text>
<text x="103.6" y="118.2">OH</text>
<text x="150.7" y="116.6">CC</text>
<text x="88.2" y="122.9">CC</text>
<text x="103.6" y="122.9">OL</text>
<text x="22" y="128.4">OL</text>
<text x="88.2" y="126">CC</text>
<text x="88.2" y="130.7">CC</text>
<text x="103.6" y="126">OL</text>
<text x="103.6" y="130.7">OL</text>
<text x="88.2" y="133.9">CC</text>
<text x="103.6" y="133.9">OL</text>
<text x="20.9" y="140.9">OZ</text>
<text x="88.2" y="138.5">O</text>
<text x="88.2" y="143.2">O</text>
<text x="95" y="138.5">CC</text>
<text x="108.2" y="143.2">CC</text>
<text x="108.8" y="138.5">CC</text>
<text x="116.1" y="147.8">CC</text>
<text x="20.9" y="154.8">CC</text>
<text x="116.1" y="152.5">CC</text>
<text x="116.1" y="157.2">CC</text>
<text x="116.1" y="161.8">CC</text>
<text x="20.9" y="179.8">CC(PD)</text>
<text x="93" y="178.2">I</text>
<text x="88.2" y="181.4">I</text>
<text x="93.8" y="181.4">CC</text>
<text x="20.9" y="197.8">IH</text>
<text x="88.2" y="197.8">I</text>
<text x="94" y="197.8">CC</text>
<text x="20.9" y="202.5">IL</text>
<text x="88.2" y="202.5">I</text>
<text x="113.9" y="207.1">CC</text>
<text x="20.9" y="212.6">lkg</text>
<text x="117.1" y="218.1">CC</text>
<text x="20.9" y="225.1">OSC</text>
<text x="88.2" y="222.8">CC</text>
<text x="88.2" y="227.4">CC</text>
<text x="88.2" y="232.1">CC</text>
<text x="20.9" y="234.4">convert</text>
<text x="46.1" y="236">OSC</text>
<text x="88.2" y="236.7">CC</text>
<text x="57.1" y="258.8">CC</text>
<text x="71.2" y="258.8">A</text>
</g>
</g></defs>
<g fill="#d8d8d8">
<path d="M19 98.6h12.2v4.7h-12.2z"/>
<path d="M31.2 98.6h31.4v4.7h-31.4z"/>
<path d="M62.6 98.6h22.7v4.7h-22.7z"/>
<path d="M85.3 98.6h27.9v4.7h-27.9z"/>
<path d="M113.2 98.6h22.6v4.7h-22.6z"/>
<path d="M135.8 98.6h10.5v4.7h-10.5z"/>
<path d="M146.3 98.6h15.7v4.7h-15.7z"/>
<path d="M162 98.6h13.9v4.7h-13.9z"/>
<path d="M175.9 98.6h10.5v4.7h-10.5z"/>
<path d="M186.4 98.6h10.4v4.7h-10.4z"/>
<path d="M19 30.6h18v13.9h-18z"/>
<path d="M37 30.6h95.2v13.9h-95.2z"/>
<path d="M132.2 39.9h23.3v4.6h-23.3z"/>
<path d="M155.5 39.9h23.4v4.6h-23.4z"/>
<path d="M178.9 30.6h17.9v13.9h-17.9z"/>
<path d="M132.2 35.2h23.3v4.7h-23.3z"/>
<path d="M155.5 35.2h23.4v4.7h-23.4z"/>
<path d="M132.2 30.6h23.3v4.6h-23.3z"/>
<path d="M155.5 30.6h23.4v4.6h-23.4z"/>
</g>
<path d="M19 22h177.8v.5h-177.8zM19 72.4l.2 .1zM132.1 72.4l.1 .1zM155.4 72.4l.1 .1zM178.8 72.4l.1 .1zM196.7 72.4l.1 .1zM19 259.7h177.8v.5h-177.8z" fill="#000"/>
<g fill="none" stroke="#000" stroke-width=".2">
<path d="M19 30.5h177.8M19.1 30.5v42M132.1 30.5v42M132.2 39.8h46.7M132.2 35.2h46.7M155.5 35.2v37.3M178.8 30.5v42M196.8 30.5v42M19 58.4h177.8M19 53.8h177.8M19 49.1h177.8M19 44.5h177.8"/>
<path d="M19 72.4h177.8M19 67.8h177.8M19 63.1h177.8M19 98.5h177.8M19.1 98.6v146.7M85.2 98.6v146.7M146.2 98.6v146.7M186.3 98.6v146.7M196.8 98.6v146.7M19 118.9h177.8M19 103.2h177.8M85.3 111h50.5"/>
<path d="M135.8 103.2v31.4M146.3 111h40.1M19 134.5h177.8M85.3 139.2h101.1M85.3 126.7h50.5M146.3 126.7h40.1M19 143.8h177.8M85.3 153.2h111.5M113.1 143.9v50M113.2 157.8h73.2M113.2 148.5h73.2M19 162.5h177.8"/>
<path d="M113.2 178.1h73.2M135.8 162.5v31.4M135.8 170.3h50.6M19 198.5h177.8M19 193.8h177.8M135.8 186h50.6M19 218.8h177.8M19 203.1h177.8M85.3 210.9h101.1M19 237.4h177.8M19 228.1h177.8M85.3 232.7h101.1"/>
<path d="M85.3 223.4h101.1M19 245.2h177.8"/>
</g>
<g fill="#231f20">
<path d="M27.5 7.6l-.1 .5 .4-.2h.6v.1v2.1l-.2 .4h1l-.3-.4v-2.1l.1-.1h.5l.5 .2-.2-.5zM29.5 8.3l.2 .3v1.5l-.2 .4h1.8l.2-.6a1.04 1.04 0 0 1-1.3 .2v-.7h.6l.3 .2v-.6l-.3 .2h-.6v-.6l.8-.1 .4 .3-.2-.5zM31.5 8.3l.9 1.1-.9 1.1h.8l-.2-.2 .5-.7 .4 .7-.2 .2h1.5l-.1-.2 .1-.4h.9l.1 .4-.2 .2h1l-.3-.3-.7-1.9h-.5l-.9 2-.8-1 .9-1h-.8l.1 .3-.3 .5-.4-.6 .2-.2zM34.7 8.6l.4 1h-.7zM36.3 8.4a.63 .63 0 0 0-.2 .7 .63 .63 0 0 0 .6 .4l.6 .2 .1 .2a.75 .75 0 0 1-.7 .4 .75 .75 0 0 1-.6-.5l.1 .7 .1-.1a1.11 1.11 0 0 0 1.5-.6 1.13 1.13 0 0 0-1.2-.8l-.1-.4a1.04 1.04 0 0 1 1.2 .2l-.2-.5-.1 .1-.5-.2zM28.2 10.9l.2 .4v2.2l-.2 .4h1l-.3-.4v-2.2l.3-.4zM29.3 11.6l.3 .4v1.5l-.3 .4h.8l-.2-.4v-1.3l1.5 1.7v-1.9l.2-.4h-.7l.2 .4v.9l-1.1-1.3zM32 11.8a.62 .62 0 0 0-.2 .7 .62 .62 0 0 0 .6 .4l.6 .1 .1 .3a.76 .76 0 0 1-.7 .3 .76 .76 0 0 1-.6-.4l.1 .7 .1-.1a1.11 1.11 0 0 0 1.5-.6 1.13 1.13 0 0 0-1.2-.8l-.1-.4a1.04 1.04 0 0 1 1.2 .2l-.2-.6-.1 .1-.5-.1zM33.7 11.6l-.2 .6a.61 .61 0 0 1 .8-.3v1.6l-.2 .4h.9l-.2-.4v-1.6a.63 .63 0 0 1 .8 .3l-.2-.6zM35.6 11.6l.3 .4v1.5l-.3 .4h1l-.2-.2v-.8l.5 .2a.76 .76 0 0 0 1.2 .7l-1-1a.58 .58 0 0 0 .6-.5 .58 .58 0 0 0-.5-.6zM36.4 11.9h.1a.45 .45 0 0 1 .5 .1 .45 .45 0 0 1 .1 .5l-.7 .2zM37.9 11.6l.2 .2a2.17 2.17 0 0 0 .3 1.9 .99 .99 0 0 0 1.6-.6v-1.1l.2-.4h-.7l.2 .2a1.92 1.92 0 0 1-.2 1.8 .6 .6 0 0 1-.9-.5v-1.1l.2-.4zM40.4 11.6l.2 .4v1.5l-.2 .4h.7l-.2-.4v-1.4l.8 1.8 .8-1.8v1.4l-.2 .4h.9l-.2-.4v-1.5l.2-.4h-.8l-.6 1.5-.6-1.5zM43.4 11.6l.2 .4v1.5l-.2 .4h1.8l.2-.6a1.04 1.04 0 0 1-1.3 .1v-.6h.5l.4 .2v-.6l-.4 .2h-.5v-.7h.8l.3 .3-.1-.6zM45.5 11.6l.2 .4v1.5l-.2 .4h.7l-.2-.4v-1.3l1.5 1.7v-1.9l.2-.4h-.7l.2 .4v.9l-1.1-1.3zM47.9 11.6l-.1 .6a.61 .61 0 0 1 .8-.3v1.6l-.3 .4h1l-.3-.4 .1-1.6a.63 .63 0 0 1 .7 .3l-.1-.6zM50.2 11.8a.62 .62 0 0 0-.2 .7 .62 .62 0 0 0 .6 .4l.6 .1 .2 .3a.76 .76 0 0 1-.8 .3 .76 .76 0 0 1-.6-.4l.1 .7 .2-.1a1.11 1.11 0 0 0 1.5-.6 1.13 1.13 0 0 0-1.3-.8l-.1-.4a1.04 1.04 0 0 1 1.2 .2l-.1-.6-.2 .1-.5-.1z"/>
<path d="M21.2 6.3v2.6h-1.9l.1 .4 .7 .9a.91 .91 0 0 0 1 .8 .56 .56 0 0 1 .5-.3 .56 .56 0 0 1 .5 .3l.4 .8a1.53 1.53 0 0 0 1.9 1.2 1.54 1.54 0 0 1 1-2.1l.9-.3v-1.4a1.52 1.52 0 0 1-.3-1.6h-1.4l-.2 .8h.5l-.2 .8h-.4l-.2 1v.2l.4 .1-.2 .8a1.93 1.93 0 0 1-1.6-.3l.3-1.8h-.5l.2-.8h.4l.2-.8h-.4v-1.3zM23.6 7.6l-.6 2.9h.7l.6-2.9zM23.8 6.6l-.1 .7h.6l.2-.7z"/>
</g>
<path d="M99.7 135.5h3.9M86.3 154.9h3.9M86.3 145.5h3.9M99.1 140.1h3.9" fill="none" stroke="#000" stroke-width=".2"/>
<use href="#words"/>
</svg>
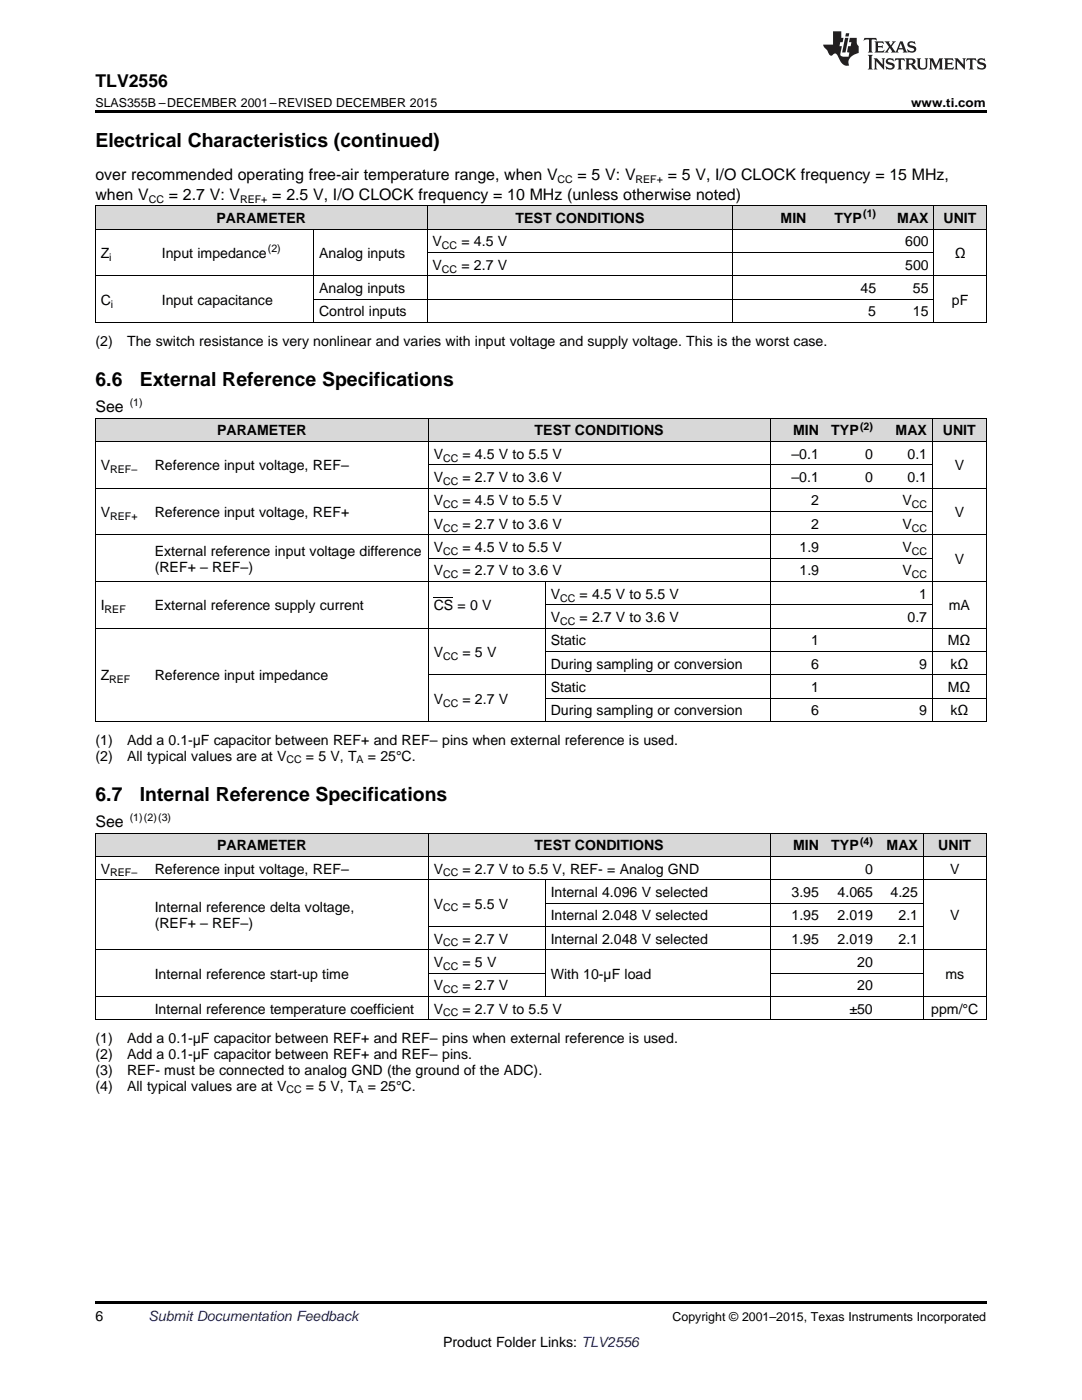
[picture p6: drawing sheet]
<svg xmlns="http://www.w3.org/2000/svg" width="216mm" height="279mm" viewBox="0 0 216 279" stroke-linecap="round" stroke-linejoin="round" font-family="sans-serif">
<defs><g id="words">
<g font-size="3.9">
<text x="19" y="29.3">Electrical Characteristics (continued)</text>
<text x="19" y="77.1">6.6</text>
<text x="27.9" y="77.1">External Reference Specifications</text>
<text x="19" y="159.9">6.7</text>
<text x="27.9" y="159.9">Internal Reference Specifications</text>
</g>
<text font-size="3.5" x="19" y="17.3">TLV2556</text>
<g font-size="3.2">
<text x="19" y="36">over recommended operating free-air temperature range, when V</text>
<text x="115.3" y="36">= 5 V: V</text>
<text x="133.2" y="36">= 5 V, I/O CLOCK frequency = 15 MHz,</text>
<text x="19" y="39.9">when V</text>
<text x="33.7" y="39.9">= 2.7 V: V</text>
<text x="54.3" y="39.9">= 2.5 V, I/O CLOCK frequency = 10 MHz (unless otherwise noted)</text>
<text x="19" y="82.2">See</text>
<text x="19" y="165">See</text>
</g>
<g font-size="2.8">
<text x="43.2" y="44.5">PARAMETER</text>
<text x="102.9" y="44.5">TEST CONDITIONS</text>
<text x="155.8" y="44.5">MIN</text>
<text x="166.5" y="44.5">TYP</text>
<text x="179" y="44.5">MAX</text>
<text x="188.3" y="44.5">UNIT</text>
<text x="20.1" y="51.5">Z</text>
<text x="32.3" y="51.5">Input impedance</text>
<text x="63.7" y="51.5">Analog inputs</text>
<text x="86.3" y="49.2">V</text>
<text x="86.3" y="53.8">V</text>
<text x="92.1" y="49.2">= 4.5 V</text>
<text x="92.1" y="53.8">= 2.7 V</text>
<text x="180.6" y="49.2">600</text>
<text x="180.6" y="53.8">500</text>
<text x="190.5" y="51.5">Ω</text>
<text x="63.7" y="58.5">Analog inputs</text>
<text x="171.7" y="58.5">45</text>
<text x="182.2" y="58.5">55</text>
<text x="20.1" y="60.8">C</text>
<text x="32.3" y="60.8">Input capacitance</text>
<text x="63.7" y="63.1">Control inputs</text>
<text x="173.2" y="63.1">5</text>
<text x="182.2" y="63.1">15</text>
<text x="189.9" y="60.8">pF</text>
<text x="19" y="69">(2)</text>
<text x="25.4" y="69">The switch resistance is very nonlinear and varies with input voltage and supply voltage. This is the worst case.</text>
<text x="43.3" y="86.9">PARAMETER</text>
<text x="106.7" y="86.9">TEST CONDITIONS</text>
<text x="158.3" y="86.9">MIN</text>
<text x="165.9" y="86.9">TYP</text>
<text x="178.7" y="86.9">MAX</text>
<text x="188.1" y="86.9">UNIT</text>
<text x="20.1" y="93.9">V</text>
<text x="30.9" y="93.9">Reference input voltage, REF–</text>
<text x="86.5" y="91.5">V</text>
<text x="92.3" y="91.5">= 4.5 V to 5.5 V</text>
<text x="157.9" y="91.5">–0.1</text>
<text x="172.6" y="91.5">0</text>
<text x="181.1" y="91.5">0.1</text>
<text x="190.5" y="93.9">V</text>
<text x="86.5" y="96.2">V</text>
<text x="86.5" y="100.9">V</text>
<text x="92.3" y="96.2">= 2.7 V to 3.6 V</text>
<text x="92.3" y="100.9">= 4.5 V to 5.5 V</text>
<text x="157.9" y="96.2">–0.1</text>
<text x="161.9" y="100.9">2</text>
<text x="172.6" y="96.2">0</text>
<text x="180.1" y="100.9">V</text>
<text x="181.1" y="96.2">0.1</text>
<text x="20.1" y="103.2">V</text>
<text x="30.9" y="103.2">Reference input voltage, REF+</text>
<text x="86.5" y="105.5">V</text>
<text x="92.3" y="105.5">= 2.7 V to 3.6 V</text>
<text x="161.9" y="105.5">2</text>
<text x="180.1" y="105.5">V</text>
<text x="190.5" y="103.2">V</text>
<text x="30.9" y="110.9">External reference input voltage difference</text>
<text x="86.5" y="110.2">V</text>
<text x="92.3" y="110.2">= 4.5 V to 5.5 V</text>
<text x="159.5" y="110.2">1.9</text>
<text x="180.1" y="110.2">V</text>
<text x="190.5" y="112.5">V</text>
<text x="30.9" y="114.1">(REF+ – REF–)</text>
<text x="86.5" y="114.8">V</text>
<text x="92.3" y="114.8">= 2.7 V to 3.6 V</text>
<text x="109.9" y="119.5">V</text>
<text x="115.6" y="119.5">= 4.5 V to 5.5 V</text>
<text x="159.5" y="114.8">1.9</text>
<text x="180.1" y="114.8">V</text>
<text x="183.4" y="119.5">1</text>
<text x="20.1" y="121.8">I</text>
<text x="30.9" y="121.8">External reference supply current</text>
<text x="86.5" y="121.8">CS = 0 V</text>
<text x="109.9" y="124.1">V</text>
<text x="115.6" y="124.1">= 2.7 V to 3.6 V</text>
<text x="181.1" y="124.1">0.7</text>
<text x="189.3" y="121.8">mA</text>
<text x="86.5" y="131.1">V</text>
<text x="92.3" y="131.1">= 5 V</text>
<text x="109.9" y="128.8">Static</text>
<text x="161.9" y="128.8">1</text>
<text x="189.2" y="128.8">MΩ</text>
<text x="20.1" y="135.8">Z</text>
<text x="30.9" y="135.8">Reference input impedance</text>
<text x="109.9" y="133.5">During sampling or conversion</text>
<text x="161.9" y="133.5">6</text>
<text x="183.4" y="133.5">9</text>
<text x="189.7" y="133.5">kΩ</text>
<text x="86.5" y="140.4">V</text>
<text x="92.3" y="140.4">= 2.7 V</text>
<text x="109.9" y="138.1">Static</text>
<text x="109.9" y="142.8">During sampling or conversion</text>
<text x="161.9" y="138.1">1</text>
<text x="161.9" y="142.8">6</text>
<text x="183.4" y="142.8">9</text>
<text x="189.2" y="138.1">MΩ</text>
<text x="189.7" y="142.8">kΩ</text>
<text x="19" y="148.6">(1)</text>
<text x="25.4" y="148.6">Add a 0.1-μF capacitor between REF+ and REF– pins when external reference is used.</text>
<text x="19" y="151.8">(2)</text>
<text x="25.4" y="151.8">All typical values are at V</text>
<text x="61" y="151.8">= 5 V, T</text>
<text x="73.4" y="151.8">= 25°C.</text>
<text x="43.3" y="169.7">PARAMETER</text>
<text x="106.7" y="169.7">TEST CONDITIONS</text>
<text x="158.3" y="169.7">MIN</text>
<text x="165.9" y="169.7">TYP</text>
<text x="176.9" y="169.7">MAX</text>
<text x="187.2" y="169.7">UNIT</text>
<text x="20.1" y="174.3">V</text>
<text x="30.9" y="174.3">Reference input voltage, REF–</text>
<text x="86.5" y="174.3">V</text>
<text x="92.3" y="174.3">= 2.7 V to 5.5 V, REF- = Analog GND</text>
<text x="109.9" y="179">Internal 4.096 V selected</text>
<text x="157.9" y="179">3.95</text>
<text x="167.1" y="179">4.065</text>
<text x="172.6" y="174.3">0</text>
<text x="177.7" y="179">4.25</text>
<text x="189.6" y="174.3">V</text>
<text x="30.9" y="182.1">Internal reference delta voltage,</text>
<text x="30.9" y="185.2">(REF+ – REF–)</text>
<text x="86.5" y="181.3">V</text>
<text x="92.3" y="181.3">= 5.5 V</text>
<text x="109.9" y="183.7">Internal 2.048 V selected</text>
<text x="157.9" y="183.7">1.95</text>
<text x="167.1" y="183.7">2.019</text>
<text x="179.3" y="183.7">2.1</text>
<text x="189.6" y="183.7">V</text>
<text x="86.5" y="188.3">V</text>
<text x="92.3" y="188.3">= 2.7 V</text>
<text x="109.9" y="188.3">Internal 2.048 V selected</text>
<text x="157.9" y="188.3">1.95</text>
<text x="167.1" y="188.3">2.019</text>
<text x="179.3" y="188.3">2.1</text>
<text x="30.9" y="195.3">Internal reference start-up time</text>
<text x="86.5" y="193">V</text>
<text x="86.5" y="197.6">V</text>
<text x="92.3" y="193">= 5 V</text>
<text x="92.3" y="197.6">= 2.7 V</text>
<text x="109.9" y="195.3">With 10-µF load</text>
<text x="171.1" y="193">20</text>
<text x="171.1" y="197.6">20</text>
<text x="188.6" y="195.3">ms</text>
<text x="30.9" y="202.3">Internal reference temperature coefficient</text>
<text x="86.5" y="202.3">V</text>
<text x="92.3" y="202.3">= 2.7 V to 5.5 V</text>
<text x="169.5" y="202.3">±50</text>
<text x="185.8" y="202.3">ppm/°C</text>
<text x="19" y="208.1">(1)</text>
<text x="25.4" y="208.1">Add a 0.1-μF capacitor between REF+ and REF– pins when external reference is used.</text>
<text x="19" y="211.3">(2)</text>
<text x="19" y="214.5">(3)</text>
<text x="25.4" y="211.3">Add a 0.1-μF capacitor between REF+ and REF– pins.</text>
<text x="25.4" y="214.5">REF- must be connected to analog GND (the ground of the ADC).</text>
<text x="19" y="217.7">(4)</text>
<text x="25.4" y="217.7">All typical values are at V</text>
<text x="61" y="217.7">= 5 V, T</text>
<text x="73.4" y="217.7">= 25°C.</text>
<text x="19" y="263.6">6</text>
<text x="88.4" y="268.9">Product Folder Links: TLV2556</text>
</g>
<text font-size="2.8" fill="#0000c8" x="29.6" y="263.6">Submit Documentation Feedback</text>
<g font-size="2.5">
<text x="19" y="21.4">SLAS355B –DECEMBER 2001–REVISED DECEMBER 2015</text>
<text x="181.8" y="21.4">www.ti.com</text>
<text x="134.2" y="263.6">Copyright © 2001–2015, Texas Instruments Incorporated</text>
</g>
<g font-size="2.1">
<text x="29.7" y="40.5">CC</text>
<text x="47.9" y="40.5">REF+</text>
<text x="111.3" y="36.6">CC</text>
<text x="126.8" y="36.6">REF+</text>
<text x="172.2" y="43.4">(1)</text>
<text x="21.8" y="52.1">i</text>
<text x="53.4" y="50.4">(2)</text>
<text x="88.2" y="49.7">CC</text>
<text x="88.2" y="54.4">CC</text>
<text x="22.1" y="61.4">i</text>
<text x="25.9" y="81">(1)</text>
<text x="171.6" y="85.8">(2)</text>
<text x="22" y="94.4">REF–</text>
<text x="88.4" y="92.1">CC</text>
<text x="88.4" y="96.8">CC</text>
<text x="88.4" y="101.4">CC</text>
<text x="181.9" y="101.4">CC</text>
<text x="22" y="103.8">REF+</text>
<text x="88.4" y="106.1">CC</text>
<text x="181.9" y="106.1">CC</text>
<text x="88.4" y="110.7">CC</text>
<text x="181.9" y="110.7">CC</text>
<text x="88.4" y="115.4">CC</text>
<text x="181.9" y="115.4">CC</text>
<text x="20.9" y="122.4">REF</text>
<text x="111.8" y="120.1">CC</text>
<text x="111.8" y="124.7">CC</text>
<text x="88.4" y="131.7">CC</text>
<text x="21.8" y="136.3">REF</text>
<text x="88.4" y="141">CC</text>
<text x="57.1" y="152.4">CC</text>
<text x="71.2" y="152.4">A</text>
<text x="25.9" y="163.8">(1)(2)(3)</text>
<text x="171.6" y="168.6">(4)</text>
<text x="22" y="174.9">REF–</text>
<text x="88.4" y="174.9">CC</text>
<text x="88.4" y="181.9">CC</text>
<text x="88.4" y="188.9">CC</text>
<text x="88.4" y="193.5">CC</text>
<text x="88.4" y="198.2">CC</text>
<text x="88.4" y="202.8">CC</text>
<text x="57.1" y="218.2">CC</text>
<text x="71.2" y="218.2">A</text>
</g>
</g></defs>
<g fill="#d8d8d8">
<path d="M19 166.3h10.8v4.7h-10.8z"/>
<path d="M29.8 166.3h55.7v4.7h-55.7z"/>
<path d="M85.5 166.3h23.3v4.7h-23.3z"/>
<path d="M108.8 166.3h44.9v4.7h-44.9z"/>
<path d="M153.7 166.3h10.8v4.7h-10.8z"/>
<path d="M164.5 166.3h10.8v4.7h-10.8z"/>
<path d="M175.3 166.3h9v4.7h-9z"/>
<path d="M184.3 166.3h12.5v4.7h-12.5z"/>
<path d="M19 83.5h10.8v4.7h-10.8z"/>
<path d="M29.8 83.5h55.7v4.7h-55.7z"/>
<path d="M85.5 83.5h23.3v4.7h-23.3z"/>
<path d="M108.8 83.5h44.9v4.7h-44.9z"/>
<path d="M153.7 83.5h10.8v4.7h-10.8z"/>
<path d="M164.5 83.5h10.8v4.7h-10.8z"/>
<path d="M175.3 83.5h10.8v4.7h-10.8z"/>
<path d="M186.1 83.5h10.7v4.7h-10.7z"/>
<path d="M19 41.1h12.2v4.7h-12.2z"/>
<path d="M31.2 41.1h31.4v4.7h-31.4z"/>
<path d="M62.6 41.1h22.7v4.7h-22.7z"/>
<path d="M85.3 41.1h27.9v4.7h-27.9z"/>
<path d="M113.2 41.1h22.6v4.7h-22.6z"/>
<path d="M135.8 41.1h10.5v4.7h-10.5z"/>
<path d="M146.3 41.1h15.7v4.7h-15.7z"/>
<path d="M162 41.1h13.9v4.7h-13.9z"/>
<path d="M175.9 41.1h10.5v4.7h-10.5z"/>
<path d="M186.4 41.1h10.4v4.7h-10.4z"/>
</g>
<g fill="#000">
<path d="M19 22h177.8v.5h-177.8zM19 64.4h.2zM62.5 64.4h.1zM85.2 64.4h.1zM113.1 64.4h.1zM135.7 64.4h.1zM146.2 64.4h.1zM161.9 64.4h.1zM175.8 64.4h.1zM186.3 64.4h.1zM196.7 64.4h.1zM19 144h.2z"/>
<path d="M85.4 144h.1zM108.7 144h.1zM153.6 144h.1zM164.4 144h.1zM175.2 144h.1zM185.9 144h.2zM196.7 144h.1zM19 203.5l.2 .1zM85.4 203.5l.1 .1zM108.7 203.5l.1 .1zM153.6 203.5l.1 .1zM164.4 203.5l.1 .1z"/>
<path d="M175.2 203.5l.1 .1zM184.1 203.5l.2 .1zM196.7 203.5l.1 .1zM19 259.7h177.8v.5h-177.8z"/>
</g>
<g fill="none" stroke="#000" stroke-width=".2">
<path d="M19 55.1h177.8M19 45.7h177.8M19 41.1h177.8M19.1 41.1v23.3M62.6 45.8v18.6M62.6 59.7h123.8M85.2 41.1v23.3M85.3 50.4h101.1M146.2 41.1v23.3M186.3 41.1v23.3M196.8 41.1v23.3M19 64.4h177.8"/>
<path d="M19 97.4h177.8M19 88.1h177.8M19 83.4h177.8M19.1 83.5v60.5M85.4 83.5v60.5M85.5 92.8h100.6M153.7 83.5v60.5M186 83.5v60.5M196.8 83.5v60.5M19 116h177.8M19 106.7h177.8M85.5 111.4h100.6"/>
<path d="M85.5 102.1h100.6M108.8 116.1v27.9M19 125.4h177.8M85.5 134.7h111.3M108.8 139.3h88M108.8 130h88M108.8 120.7h77.3M19 144h177.8M19 175.6h177.8M19 170.9h177.8M19 166.2h177.8M19.1 166.3v37.3"/>
<path d="M85.4 166.3v37.3M108.8 175.6v23.3M153.7 166.3v37.3M184.2 166.3v37.3M196.8 166.3v37.3M19 198.8h177.8M19 189.5h177.8M85.5 194.2h23.3M85.5 184.9h98.8M108.8 180.2h75.5M153.7 194.2h30.6M19 203.5h177.8"/>
</g>
<g fill="#231f20">
<path d="M172.5 7.6l-.1 .5 .4-.2h.6v.1v2.1l-.2 .4h.9l-.2-.4v-2.1l.1-.1h.5l.5 .2-.2-.5zM174.5 8.3l.2 .3v1.5l-.2 .4h1.8l.2-.6a1.04 1.04 0 0 1-1.3 .2v-.7h.6l.3 .2v-.6l-.3 .2h-.6v-.6l.8-.1 .4 .3-.2-.5zM176.5 8.3l.9 1.1-.9 1.1h.8l-.2-.2 .4-.7 .5 .7-.2 .2h1.5l-.2-.2 .2-.4h.9l.1 .4-.2 .2h1l-.3-.3-.7-1.9h-.5l-.9 2-.8-1 .9-1h-.8l.1 .3-.4 .5-.3-.6 .1-.2zM179.7 8.6l.4 1h-.7zM181.3 8.4a.63 .63 0 0 0-.2 .7 .63 .63 0 0 0 .6 .4l.6 .2 .1 .2a.75 .75 0 0 1-.7 .4 .75 .75 0 0 1-.6-.5l.1 .7 .1-.1a1.11 1.11 0 0 0 1.5-.6 1.13 1.13 0 0 0-1.2-.8l-.1-.4a1.04 1.04 0 0 1 1.2 .2l-.2-.5-.2 .1-.4-.2zM173.2 10.9l.2 .4v2.2l-.2 .4h1l-.3-.4v-2.2l.3-.4zM174.3 11.6l.3 .4v1.5l-.3 .4h.8l-.2-.4v-1.3l1.5 1.7v-1.9l.2-.4h-.7l.2 .4v.9l-1.1-1.3zM177 11.8a.62 .62 0 0 0-.2 .7 .62 .62 0 0 0 .6 .4l.6 .1 .1 .3a.76 .76 0 0 1-.7 .3 .76 .76 0 0 1-.7-.4l.2 .7 .1-.1a1.11 1.11 0 0 0 1.5-.6 1.13 1.13 0 0 0-1.2-.8l-.1-.4a1.04 1.04 0 0 1 1.2 .2l-.2-.6-.2 .1-.5-.1zM178.7 11.6l-.2 .6a.61 .61 0 0 1 .8-.3v1.6l-.2 .4h.9l-.2-.4v-1.6a.63 .63 0 0 1 .7 .3l-.1-.6zM180.6 11.6l.3 .4v1.5l-.3 .4h1l-.2-.2-.1-.8 .6 .2a.76 .76 0 0 0 1.2 .7l-1-1a.58 .58 0 0 0 .6-.5 .58 .58 0 0 0-.5-.6zM181.4 11.9h.1a.45 .45 0 0 1 .5 .1 .45 .45 0 0 1 .1 .5l-.8 .2zM182.9 11.6l.2 .2a2.17 2.17 0 0 0 .3 1.9 .99 .99 0 0 0 1.6-.6v-1.1l.2-.4h-.7l.2 .2a1.92 1.92 0 0 1-.2 1.8 .6 .6 0 0 1-.9-.5v-1.1l.2-.4zM185.4 11.6l.2 .4v1.5l-.2 .4h.7l-.2-.4v-1.4l.8 1.8 .8-1.8v1.4l-.2 .4h.9l-.2-.4v-1.5l.2-.4h-.8l-.6 1.5-.6-1.5zM188.4 11.6l.2 .4v1.5l-.2 .4h1.8l.1-.6a1.04 1.04 0 0 1-1.2 .1v-.6h.5l.4 .2v-.6l-.4 .2h-.5v-.7h.8l.3 .3-.1-.6zM190.5 11.6l.2 .4v1.5l-.2 .4h.7l-.2-.4v-1.3l1.5 1.7v-1.9l.2-.4h-.7l.2 .4v.9l-1.1-1.3zM192.9 11.6l-.1 .6a.61 .61 0 0 1 .7-.3l.1 1.6-.3 .4h1l-.3-.4 .1-1.6a.63 .63 0 0 1 .7 .3l-.1-.6zM195.2 11.8a.62 .62 0 0 0-.2 .7 .62 .62 0 0 0 .6 .4l.6 .1 .1 .3a.76 .76 0 0 1-.7 .3 .76 .76 0 0 1-.6-.4l.1 .7 .1-.1a1.11 1.11 0 0 0 1.6-.6 1.13 1.13 0 0 0-1.3-.8l-.1-.4a1.04 1.04 0 0 1 1.2 .2l-.1-.6-.2 .1-.5-.1z"/>
<path d="M166.2 6.3v2.6h-1.9v.4l.8 .9a.91 .91 0 0 0 1 .8 .56 .56 0 0 1 .5-.3 .56 .56 0 0 1 .5 .3l.4 .8a1.53 1.53 0 0 0 1.9 1.2 1.54 1.54 0 0 1 1-2.1l.9-.3v-1.4a1.52 1.52 0 0 1-.4-1.6h-1.3l-.2 .8h.5l-.2 .8h-.5l-.1 1v.2l.4 .1-.2 .8a1.93 1.93 0 0 1-1.6-.3l.3-1.8h-.5l.2-.8h.4l.2-.8h-.4v-1.3zM168.6 7.6l-.6 2.9h.7l.6-2.9zM168.8 6.6l-.1 .7h.6l.2-.7z"/>
</g>
<path d="M86.5 119.3h4" fill="none" stroke="#000" stroke-width=".2"/>
<use href="#words"/>
</svg>
